VERSION 5.8 ;
BUSBITCHARS "[]" ;
DIVIDERCHAR "/" ;
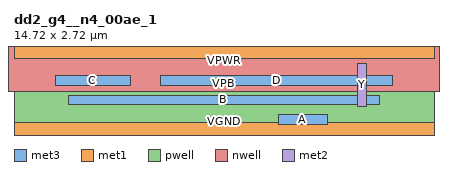
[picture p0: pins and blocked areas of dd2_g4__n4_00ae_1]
MACRO dd2_g4__n4_00ae_1
  CLASS CORE ;
  ORIGIN 0 0 ;
  SIZE 14.720 BY 2.720 ;
  SYMMETRY X Y ;
  SITE unithd ;
  PIN A
    DIRECTION INPUT ;
    USE SIGNAL ;
    ANTENNAGATEAREA 0.213000 ;
    PORT
      LAYER met3 ;
        RECT 9.265 0.175 10.975 0.505 ;
    END
  END A
  PIN B
    DIRECTION INPUT ;
    USE SIGNAL ;
    ANTENNAGATEAREA 0.213000 ;
    PORT
      LAYER met3 ;
        RECT 1.905 0.855 12.815 1.185 ;
    END
  END B
  PIN C
    DIRECTION INPUT ;
    USE SIGNAL ;
    ANTENNAGATEAREA 0.213000 ;
    PORT
      LAYER met3 ;
        RECT 1.445 1.535 4.075 1.865 ;
    END
  END C
  PIN D
    DIRECTION INPUT ;
    USE SIGNAL ;
    ANTENNAGATEAREA 0.213000 ;
    PORT
      LAYER met3 ;
        RECT 5.125 1.535 13.275 1.865 ;
    END
  END D
  PIN VGND
    DIRECTION INOUT ;
    USE GROUND ;
    SHAPE ABUTMENT ;
    PORT
      LAYER met1 ;
        RECT 0.000 -0.240 14.720 0.240 ;
    END
  END VGND
  PIN VNB
    DIRECTION INOUT ;
    USE GROUND ;
    PORT
      LAYER pwell ;
        RECT 0.000 0.000 14.720 1.305 ;
    END
  END VNB
  PIN VPB
    DIRECTION INOUT ;
    USE POWER ;
    PORT
      LAYER nwell ;
        RECT -0.190 1.305 14.910 2.910 ;
    END
  END VPB
  PIN VPWR
    DIRECTION INOUT ;
    USE POWER ;
    SHAPE ABUTMENT ;
    PORT
      LAYER met1 ;
        RECT 0.000 2.480 14.720 2.960 ;
    END
  END VPWR
  PIN Y
    DIRECTION OUTPUT ;
    USE SIGNAL ;
    ANTENNADIFFAREA 1.699800 ;
    PORT
      LAYER met2 ;
        RECT 12.030 0.790 12.350 2.305 ;
    END
  END Y
  OBS
    LAYER li1 ;
      RECT 0.000 -0.085 14.720 0.085 ;
      RECT 0.605 0.085 0.775 0.565 ;
      RECT 4.285 0.085 4.455 0.565 ;
      RECT 11.645 0.085 11.815 0.565 ;
      RECT 2.365 0.255 2.695 0.710 ;
      RECT 6.045 0.255 6.375 0.710 ;
      RECT 7.885 0.255 8.215 0.710 ;
      RECT 9.725 0.255 10.055 0.710 ;
      RECT 13.405 0.255 13.735 0.710 ;
      RECT 1.525 0.380 1.695 1.075 ;
      RECT 1.405 1.075 1.735 1.245 ;
      RECT 3.365 0.380 3.535 1.075 ;
      RECT 3.245 1.075 3.575 1.245 ;
      RECT 5.205 0.380 5.375 1.075 ;
      RECT 5.085 1.075 5.415 1.245 ;
      RECT 7.045 0.380 7.215 1.075 ;
      RECT 6.925 1.075 7.255 1.245 ;
      RECT 10.725 0.380 10.895 1.075 ;
      RECT 10.605 1.075 10.935 1.245 ;
      RECT 12.565 0.380 12.735 1.075 ;
      RECT 12.445 1.075 12.775 1.245 ;
      RECT 1.945 1.075 2.275 1.245 ;
      RECT 1.985 1.245 2.155 2.340 ;
      RECT 3.785 1.075 4.115 1.245 ;
      RECT 3.825 1.245 3.995 2.340 ;
      RECT 5.625 1.075 5.955 1.245 ;
      RECT 5.665 1.245 5.835 2.340 ;
      RECT 7.465 1.075 7.795 1.245 ;
      RECT 7.505 1.245 7.675 2.340 ;
      RECT 9.305 1.075 9.635 1.245 ;
      RECT 9.345 1.245 9.515 2.340 ;
      RECT 12.985 1.075 13.315 1.245 ;
      RECT 13.025 1.245 13.195 2.340 ;
      RECT 0.985 1.505 1.315 2.465 ;
      RECT 6.505 1.505 6.835 2.465 ;
      RECT 10.185 1.505 10.515 2.465 ;
      RECT 12.025 1.505 12.355 2.465 ;
      RECT 13.865 1.505 14.195 2.465 ;
      RECT 2.905 1.495 3.075 2.635 ;
      RECT 8.425 1.495 8.595 2.635 ;
      RECT 0.000 2.635 14.720 2.805 ;
    LAYER met1 ;
      RECT 1.465 0.380 1.755 0.710 ;
      RECT 2.365 0.380 2.695 0.710 ;
      RECT 3.305 0.380 3.595 0.710 ;
      RECT 5.145 0.380 5.435 0.710 ;
      RECT 6.985 0.380 7.275 0.710 ;
      RECT 7.885 0.380 8.215 0.710 ;
      RECT 9.725 0.380 10.055 0.710 ;
      RECT 10.665 0.380 10.955 0.710 ;
      RECT 12.505 0.380 12.795 0.710 ;
      RECT 13.405 0.380 13.735 0.710 ;
      RECT 6.045 0.380 6.375 0.710 ;
      RECT 6.050 0.710 6.370 0.850 ;
      RECT 12.030 0.790 12.350 0.850 ;
      RECT 6.045 0.850 12.355 0.990 ;
      RECT 6.050 0.990 6.370 1.050 ;
      RECT 12.030 0.990 12.350 1.050 ;
      RECT 6.970 1.230 7.290 1.290 ;
      RECT 7.430 1.230 7.750 1.290 ;
      RECT 9.730 1.230 10.050 1.290 ;
      RECT 10.190 1.230 10.510 1.290 ;
      RECT 6.965 1.290 10.515 1.430 ;
      RECT 6.970 1.430 7.290 1.490 ;
      RECT 7.430 1.430 7.750 1.490 ;
      RECT 9.730 1.430 10.050 1.490 ;
      RECT 10.190 1.430 10.510 1.490 ;
      RECT 1.925 2.010 2.215 2.340 ;
      RECT 3.765 2.010 4.055 2.340 ;
      RECT 0.990 1.670 1.310 1.730 ;
      RECT 3.290 1.670 3.610 1.730 ;
      RECT 5.590 1.670 5.910 1.730 ;
      RECT 13.410 1.670 13.730 1.730 ;
      RECT 0.985 1.730 13.735 1.870 ;
      RECT 3.290 1.870 3.610 1.930 ;
      RECT 5.590 1.870 5.910 1.930 ;
      RECT 13.410 1.870 13.730 1.930 ;
      RECT 0.990 1.870 1.310 2.010 ;
      RECT 5.595 1.930 5.905 2.175 ;
      RECT 0.985 2.010 1.315 2.340 ;
      RECT 5.605 2.175 5.895 2.340 ;
      RECT 6.505 2.010 6.835 2.340 ;
      RECT 7.445 2.010 7.735 2.340 ;
      RECT 9.285 2.010 9.575 2.340 ;
      RECT 10.185 2.010 10.515 2.340 ;
      RECT 12.025 2.010 12.355 2.340 ;
      RECT 12.965 2.010 13.255 2.340 ;
      RECT 13.865 2.010 14.195 2.340 ;
    LAYER met2 ;
      RECT 2.390 0.155 2.670 0.210 ;
      RECT 2.370 0.210 2.690 0.675 ;
      RECT 7.910 0.155 8.190 0.210 ;
      RECT 7.890 0.210 8.210 0.675 ;
      RECT 10.670 0.155 10.950 0.210 ;
      RECT 10.650 0.210 10.970 0.675 ;
      RECT 6.050 0.415 6.370 1.050 ;
      RECT 12.490 0.415 12.810 1.150 ;
      RECT 12.510 1.150 12.790 1.205 ;
      RECT 6.970 0.415 7.290 1.490 ;
      RECT 9.730 0.415 10.050 1.490 ;
      RECT 1.450 0.415 1.770 1.830 ;
      RECT 1.470 1.830 1.750 1.885 ;
      RECT 5.130 0.415 5.450 1.830 ;
      RECT 5.150 1.830 5.430 1.885 ;
      RECT 3.290 0.415 3.610 1.930 ;
      RECT 13.410 0.415 13.730 1.930 ;
      RECT 0.990 1.670 1.310 2.305 ;
      RECT 1.930 0.835 2.210 0.890 ;
      RECT 1.910 0.890 2.230 2.305 ;
      RECT 3.770 1.515 4.050 1.570 ;
      RECT 3.750 1.570 4.070 2.305 ;
      RECT 5.590 1.670 5.910 2.305 ;
      RECT 7.430 1.230 7.750 2.305 ;
      RECT 9.290 0.155 9.570 0.210 ;
      RECT 9.270 0.210 9.590 2.305 ;
      RECT 10.190 1.230 10.510 2.305 ;
      RECT 12.970 1.515 13.250 1.570 ;
      RECT 12.950 1.570 13.270 2.305 ;
      RECT 6.510 2.045 6.830 2.510 ;
      RECT 6.530 2.510 6.810 2.565 ;
      RECT 13.870 2.045 14.190 2.510 ;
      RECT 13.890 2.510 14.170 2.565 ;
    LAYER met3 ;
      RECT 2.365 0.175 8.215 0.505 ;
      RECT 6.505 2.215 14.195 2.545 ;
  END
END dd2_g4__n4_00ae_1
END LIBRARY
